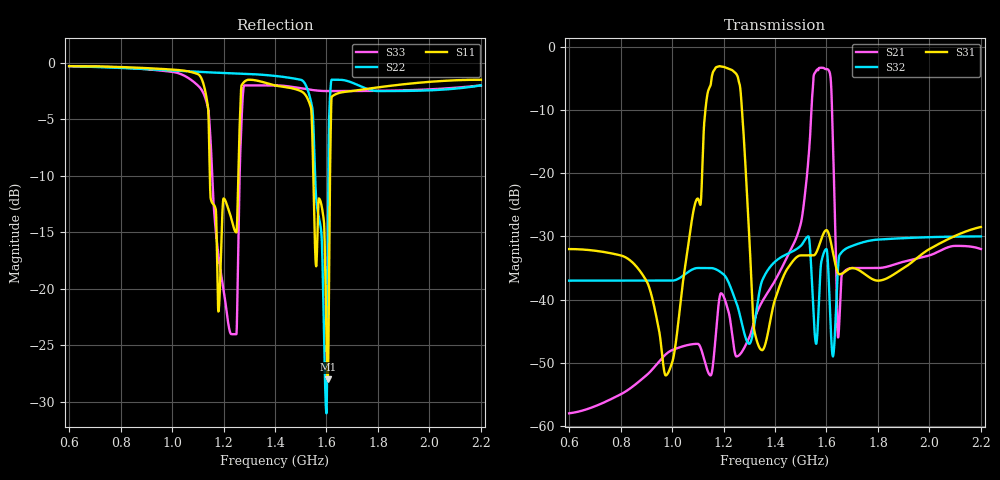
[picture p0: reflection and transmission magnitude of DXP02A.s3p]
! Project 16: GNSS L1 + L2/L5 active antenna front end (RFMW-ANT)
! Generated by Scripts/simulate.py from Scripts/ds_data.py; format GHz / RI, Z0 = 50 ohm
! ESTIMATED from Taoglas DXP.02.A datasheet SPE-17-8-007-E plots p.6-8 (eval-board matching L2/C1/L1/L3/C2 included).
! Port 1 = common (pin 2), port 2 = L1 (pin 7), port 3 = L2/L5 (pin 5).
! Minimum-phase transmission; reflection phase [ASSUMED]. NOT measured data.
# GHz S RI R 50.0
!freq ReS11 ImS11 ReS12 ImS12 ReS13 ImS13
! ReS21 ImS21 ReS22 ImS22 ReS23 ImS23
! ReS31 ImS31 ReS32 ImS32 ReS33 ImS33
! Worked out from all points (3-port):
!   3201 points, 600 MHz to 2.2 GHz, reference 50 ohm
!   strongest paths, dB at 600 MHz, 1 GHz, 1.4 GHz, 1.8 GHz, 2.2 GHz:
!     S31: -32.0, -50.0, -40.0, -37.0, -28.5
!     S32: -37.0, -37.0, -34.0, -30.5, -30.0
!     S21: -58.0, -48.0, -37.0, -35.0, -32.0
!   lowest |S11| = -28.0 dB at 1.605 GHz (marker M1), VSWR 1.08, Z = 49.7 + j3.97 ohm
!   |S11| at or under -10 dB: 1.147 GHz to 1.257 GHz (110.6 MHz wide, 9.2 % of centre); 1.549 GHz to 1.614 GHz (64.97 MHz wide, 4.11 % of centre)
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0.6  -0.0213 0.9658  0.00034 0.00121  0.0251 0.000555
     0.00034 0.00121  -0.1817 0.9488  0.0139 0.00266
     0.0251 0.000555  0.0139 0.00266  -0.0213 0.9658
0.9545  0.2359 0.91  -0.00242 0.00228  0.00472 -0.00122
        -0.00242 0.00228  -0.3208 0.874  0.0133 0.00487
        0.00472 -0.00122  0.0133 0.00487  -0.3185 0.8675
0.9815  -0.662 -0.6619  -0.00267 0.00267  0.00152 0.00207
        -0.00267 0.00267  -0.3419 0.8623  0.0131 0.00521
        0.00152 0.00207  0.0131 0.00521  -0.3381 0.8525
1.2005  -0.00537 0.2511  -0.0079 0.00704  0.6953 0.0149
        -0.0079 0.00704  -0.00979 0.9018  0.0158 0.000172
        0.6953 0.0149  0.0158 0.000172  -0.00212 0.0992
1.284  -0.4579 -0.6923  -0.00422 0.000741  -0.1059 0.0701
       -0.00422 0.000741  -0.2186 0.8672  0.00497 0.00125
       -0.1059 0.0701  0.00497 0.00125  -0.4382 -0.6625
1.3005  -0.582 -0.6076  -0.00504 -0.000123  -0.0219 0.021
        -0.00504 -0.000123  0.0217 -0.8921  0.00323 0.00309
        -0.0219 0.021  0.00323 0.00309  -0.5495 -0.5736
1.4  0.1963 -0.7697  -0.0137 -0.00349  0.00991 0.00133
     -0.0137 -0.00349  -0.7744 0.4073  0.00929 0.0177
     0.00991 0.00133  0.00929 0.0177  -0.703 0.3698
1.605  -0.000973 0.0398  0.6643 0.0162  0.0335 -0.00901
       0.6643 0.0162  -0.00281 0.1152  0.0205 -0.000493
       0.0335 -0.00901  0.0205 -0.000493  0.1948 0.7241
1.647  0.2224 0.6999  0.00476 -0.00231  0.0152 -0.00484
       0.00476 -0.00231  -0.7961 -0.2725  -0.00662 0.0194
       0.0152 -0.00484  -0.00662 0.0194  -0.7095 -0.2428
2.2  -0.4389 0.7179  0.0146 0.0205  0.0321 0.0196
     0.0146 0.0205  -0.3786 0.6983  0.0278 0.0151
     0.0321 0.0196  0.0278 0.0151  -0.4144 0.6777
